VERSION 5.7 ;
  NOWIREEXTENSIONATPIN ON ;
  DIVIDERCHAR "/" ;
  BUSBITCHARS "[]" ;
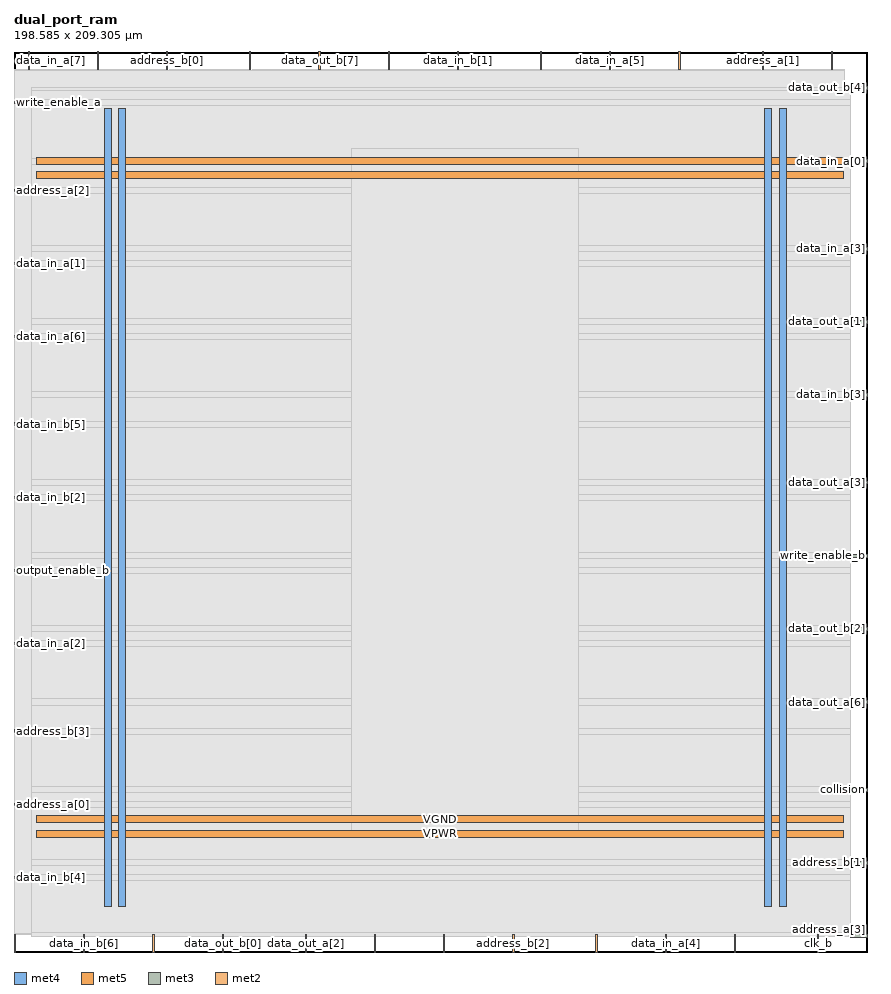
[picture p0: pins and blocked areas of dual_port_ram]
MACRO dual_port_ram
  CLASS BLOCK ;
  FOREIGN dual_port_ram ;
  ORIGIN 0.000 0.000 ;
  SIZE 198.585 BY 209.305 ;
  PIN VGND
    DIRECTION INOUT ;
    USE GROUND ;
    PORT
      LAYER met4 ;
        RECT 24.340 10.640 25.940 196.080 ;
    END
    PORT
      LAYER met4 ;
        RECT 177.940 10.640 179.540 196.080 ;
    END
    PORT
      LAYER met5 ;
        RECT 5.280 30.030 192.980 31.630 ;
    END
    PORT
      LAYER met5 ;
        RECT 5.280 183.210 192.980 184.810 ;
    END
  END VGND
  PIN VPWR
    DIRECTION INOUT ;
    USE POWER ;
    PORT
      LAYER met4 ;
        RECT 21.040 10.640 22.640 196.080 ;
    END
    PORT
      LAYER met4 ;
        RECT 174.640 10.640 176.240 196.080 ;
    END
    PORT
      LAYER met5 ;
        RECT 5.280 26.730 192.980 28.330 ;
    END
    PORT
      LAYER met5 ;
        RECT 5.280 179.910 192.980 181.510 ;
    END
  END VPWR
  PIN address_a[0]
    DIRECTION INPUT ;
    USE SIGNAL ;
    ANTENNAGATEAREA 0.247500 ;
    PORT
      LAYER met3 ;
        RECT 0.000 34.040 4.000 34.640 ;
    END
  END address_a[0]
  PIN address_a[1]
    DIRECTION INPUT ;
    USE SIGNAL ;
    ANTENNAGATEAREA 0.247500 ;
    PORT
      LAYER met2 ;
        RECT 173.970 205.305 174.250 209.305 ;
    END
  END address_a[1]
  PIN address_a[2]
    DIRECTION INPUT ;
    USE SIGNAL ;
    ANTENNAGATEAREA 0.213000 ;
    PORT
      LAYER met3 ;
        RECT 0.000 176.840 4.000 177.440 ;
    END
  END address_a[2]
  PIN address_a[3]
    DIRECTION INPUT ;
    USE SIGNAL ;
    ANTENNAGATEAREA 0.159000 ;
    PORT
      LAYER met3 ;
        RECT 194.585 3.440 198.585 4.040 ;
    END
  END address_a[3]
  PIN address_b[0]
    DIRECTION INPUT ;
    USE SIGNAL ;
    ANTENNAGATEAREA 0.213000 ;
    PORT
      LAYER met2 ;
        RECT 35.510 205.305 35.790 209.305 ;
    END
  END address_b[0]
  PIN address_b[1]
    DIRECTION INPUT ;
    USE SIGNAL ;
    ANTENNAGATEAREA 0.213000 ;
    PORT
      LAYER met3 ;
        RECT 194.585 20.440 198.585 21.040 ;
    END
  END address_b[1]
  PIN address_b[2]
    DIRECTION INPUT ;
    USE SIGNAL ;
    ANTENNAGATEAREA 0.159000 ;
    PORT
      LAYER met2 ;
        RECT 116.010 0.000 116.290 4.000 ;
    END
  END address_b[2]
  PIN address_b[3]
    DIRECTION INPUT ;
    USE SIGNAL ;
    ANTENNAGATEAREA 0.213000 ;
    PORT
      LAYER met3 ;
        RECT 0.000 51.040 4.000 51.640 ;
    END
  END address_b[3]
  PIN clk_a
    DIRECTION INPUT ;
    USE SIGNAL ;
    ANTENNAGATEAREA 0.852000 ;
    PORT
      LAYER met2 ;
        RECT 19.410 205.305 19.690 209.305 ;
    END
  END clk_a
  PIN clk_b
    DIRECTION INPUT ;
    USE SIGNAL ;
    ANTENNAGATEAREA 0.196500 ;
    PORT
      LAYER met2 ;
        RECT 186.850 0.000 187.130 4.000 ;
    END
  END clk_b
  PIN collision
    DIRECTION OUTPUT TRISTATE ;
    USE SIGNAL ;
    ANTENNADIFFAREA 0.445500 ;
    PORT
      LAYER met3 ;
        RECT 194.585 37.440 198.585 38.040 ;
    END
  END collision
  PIN data_in_a[0]
    DIRECTION INPUT ;
    USE SIGNAL ;
    ANTENNAGATEAREA 0.213000 ;
    PORT
      LAYER met3 ;
        RECT 194.585 183.640 198.585 184.240 ;
    END
  END data_in_a[0]
  PIN data_in_a[1]
    DIRECTION INPUT ;
    USE SIGNAL ;
    ANTENNAGATEAREA 0.213000 ;
    PORT
      LAYER met3 ;
        RECT 0.000 159.840 4.000 160.440 ;
    END
  END data_in_a[1]
  PIN data_in_a[2]
    DIRECTION INPUT ;
    USE SIGNAL ;
    ANTENNAGATEAREA 0.159000 ;
    PORT
      LAYER met3 ;
        RECT 0.000 71.440 4.000 72.040 ;
    END
  END data_in_a[2]
  PIN data_in_a[3]
    DIRECTION INPUT ;
    USE SIGNAL ;
    ANTENNAGATEAREA 0.213000 ;
    PORT
      LAYER met3 ;
        RECT 194.585 163.240 198.585 163.840 ;
    END
  END data_in_a[3]
  PIN data_in_a[4]
    DIRECTION INPUT ;
    USE SIGNAL ;
    ANTENNAGATEAREA 0.159000 ;
    PORT
      LAYER met2 ;
        RECT 151.430 0.000 151.710 4.000 ;
    END
  END data_in_a[4]
  PIN data_in_a[5]
    DIRECTION INPUT ;
    USE SIGNAL ;
    ANTENNAGATEAREA 0.213000 ;
    PORT
      LAYER met2 ;
        RECT 138.550 205.305 138.830 209.305 ;
    END
  END data_in_a[5]
  PIN data_in_a[6]
    DIRECTION INPUT ;
    USE SIGNAL ;
    ANTENNAGATEAREA 0.213000 ;
    PORT
      LAYER met3 ;
        RECT 0.000 142.840 4.000 143.440 ;
    END
  END data_in_a[6]
  PIN data_in_a[7]
    DIRECTION INPUT ;
    USE SIGNAL ;
    ANTENNAGATEAREA 0.159000 ;
    PORT
      LAYER met2 ;
        RECT 3.310 205.305 3.590 209.305 ;
    END
  END data_in_a[7]
  PIN data_in_b[0]
    DIRECTION INPUT ;
    USE SIGNAL ;
    ANTENNAGATEAREA 0.159000 ;
    PORT
      LAYER met2 ;
        RECT 154.650 205.305 154.930 209.305 ;
    END
  END data_in_b[0]
  PIN data_in_b[1]
    DIRECTION INPUT ;
    USE SIGNAL ;
    ANTENNAGATEAREA 0.159000 ;
    PORT
      LAYER met2 ;
        RECT 103.130 205.305 103.410 209.305 ;
    END
  END data_in_b[1]
  PIN data_in_b[2]
    DIRECTION INPUT ;
    USE SIGNAL ;
    ANTENNAGATEAREA 0.159000 ;
    PORT
      LAYER met3 ;
        RECT 0.000 105.440 4.000 106.040 ;
    END
  END data_in_b[2]
  PIN data_in_b[3]
    DIRECTION INPUT ;
    USE SIGNAL ;
    ANTENNAGATEAREA 0.213000 ;
    PORT
      LAYER met3 ;
        RECT 194.585 129.240 198.585 129.840 ;
    END
  END data_in_b[3]
  PIN data_in_b[4]
    DIRECTION INPUT ;
    USE SIGNAL ;
    ANTENNAGATEAREA 0.213000 ;
    PORT
      LAYER met3 ;
        RECT 0.000 17.040 4.000 17.640 ;
    END
  END data_in_b[4]
  PIN data_in_b[5]
    DIRECTION INPUT ;
    USE SIGNAL ;
    ANTENNAGATEAREA 0.159000 ;
    PORT
      LAYER met3 ;
        RECT 0.000 122.440 4.000 123.040 ;
    END
  END data_in_b[5]
  PIN data_in_b[6]
    DIRECTION INPUT ;
    USE SIGNAL ;
    ANTENNAGATEAREA 0.159000 ;
    PORT
      LAYER met2 ;
        RECT 16.190 0.000 16.470 4.000 ;
    END
  END data_in_b[6]
  PIN data_in_b[7]
    DIRECTION INPUT ;
    USE SIGNAL ;
    ANTENNAGATEAREA 0.159000 ;
    PORT
      LAYER met2 ;
        RECT 0.090 0.000 0.370 4.000 ;
    END
  END data_in_b[7]
  PIN data_out_a[0]
    DIRECTION OUTPUT TRISTATE ;
    USE SIGNAL ;
    ANTENNADIFFAREA 0.795200 ;
    PORT
      LAYER met2 ;
        RECT 87.030 205.305 87.310 209.305 ;
    END
  END data_out_a[0]
  PIN data_out_a[1]
    DIRECTION OUTPUT TRISTATE ;
    USE SIGNAL ;
    ANTENNADIFFAREA 0.445500 ;
    PORT
      LAYER met3 ;
        RECT 194.585 146.240 198.585 146.840 ;
    END
  END data_out_a[1]
  PIN data_out_a[2]
    DIRECTION OUTPUT TRISTATE ;
    USE SIGNAL ;
    ANTENNADIFFAREA 0.795200 ;
    PORT
      LAYER met2 ;
        RECT 67.710 0.000 67.990 4.000 ;
    END
  END data_out_a[2]
  PIN data_out_a[3]
    DIRECTION OUTPUT TRISTATE ;
    USE SIGNAL ;
    ANTENNADIFFAREA 0.445500 ;
    PORT
      LAYER met3 ;
        RECT 194.585 108.840 198.585 109.440 ;
    END
  END data_out_a[3]
  PIN data_out_a[4]
    DIRECTION OUTPUT TRISTATE ;
    USE SIGNAL ;
    ANTENNADIFFAREA 0.795200 ;
    PORT
      LAYER met2 ;
        RECT 167.530 0.000 167.810 4.000 ;
    END
  END data_out_a[4]
  PIN data_out_a[5]
    DIRECTION OUTPUT TRISTATE ;
    USE SIGNAL ;
    ANTENNADIFFAREA 0.795200 ;
    PORT
      LAYER met2 ;
        RECT 122.450 205.305 122.730 209.305 ;
    END
  END data_out_a[5]
  PIN data_out_a[6]
    DIRECTION OUTPUT TRISTATE ;
    USE SIGNAL ;
    ANTENNADIFFAREA 0.445500 ;
    PORT
      LAYER met3 ;
        RECT 194.585 57.840 198.585 58.440 ;
    END
  END data_out_a[6]
  PIN data_out_a[7]
    DIRECTION OUTPUT TRISTATE ;
    USE SIGNAL ;
    ANTENNADIFFAREA 0.795200 ;
    PORT
      LAYER met2 ;
        RECT 32.290 0.000 32.570 4.000 ;
    END
  END data_out_a[7]
  PIN data_out_b[0]
    DIRECTION OUTPUT TRISTATE ;
    USE SIGNAL ;
    ANTENNADIFFAREA 0.795200 ;
    PORT
      LAYER met2 ;
        RECT 48.390 0.000 48.670 4.000 ;
    END
  END data_out_b[0]
  PIN data_out_b[1]
    DIRECTION OUTPUT TRISTATE ;
    USE SIGNAL ;
    ANTENNADIFFAREA 0.795200 ;
    PORT
      LAYER met2 ;
        RECT 83.810 0.000 84.090 4.000 ;
    END
  END data_out_b[1]
  PIN data_out_b[2]
    DIRECTION OUTPUT TRISTATE ;
    USE SIGNAL ;
    ANTENNADIFFAREA 0.795200 ;
    PORT
      LAYER met3 ;
        RECT 194.585 74.840 198.585 75.440 ;
    END
  END data_out_b[2]
  PIN data_out_b[3]
    DIRECTION OUTPUT TRISTATE ;
    USE SIGNAL ;
    ANTENNADIFFAREA 0.795200 ;
    PORT
      LAYER met2 ;
        RECT 99.910 0.000 100.190 4.000 ;
    END
  END data_out_b[3]
  PIN data_out_b[4]
    DIRECTION OUTPUT TRISTATE ;
    USE SIGNAL ;
    ANTENNADIFFAREA 0.795200 ;
    PORT
      LAYER met3 ;
        RECT 194.585 200.640 198.585 201.240 ;
    END
  END data_out_b[4]
  PIN data_out_b[5]
    DIRECTION OUTPUT TRISTATE ;
    USE SIGNAL ;
    ANTENNADIFFAREA 0.445500 ;
    PORT
      LAYER met2 ;
        RECT 190.070 205.305 190.350 209.305 ;
    END
  END data_out_b[5]
  PIN data_out_b[6]
    DIRECTION OUTPUT TRISTATE ;
    USE SIGNAL ;
    ANTENNADIFFAREA 0.795200 ;
    PORT
      LAYER met2 ;
        RECT 54.830 205.305 55.110 209.305 ;
    END
  END data_out_b[6]
  PIN data_out_b[7]
    DIRECTION OUTPUT TRISTATE ;
    USE SIGNAL ;
    ANTENNADIFFAREA 0.795200 ;
    PORT
      LAYER met2 ;
        RECT 70.930 205.305 71.210 209.305 ;
    END
  END data_out_b[7]
  PIN output_enable_a
    DIRECTION INPUT ;
    USE SIGNAL ;
    ANTENNAGATEAREA 0.247500 ;
    PORT
      LAYER met2 ;
        RECT 135.330 0.000 135.610 4.000 ;
    END
  END output_enable_a
  PIN output_enable_b
    DIRECTION INPUT ;
    USE SIGNAL ;
    ANTENNAGATEAREA 0.213000 ;
    PORT
      LAYER met3 ;
        RECT 0.000 88.440 4.000 89.040 ;
    END
  END output_enable_b
  PIN write_enable_a
    DIRECTION INPUT ;
    USE SIGNAL ;
    ANTENNAGATEAREA 0.159000 ;
    PORT
      LAYER met3 ;
        RECT 0.000 197.240 4.000 197.840 ;
    END
  END write_enable_a
  PIN write_enable_b
    DIRECTION INPUT ;
    USE SIGNAL ;
    ANTENNAGATEAREA 0.213000 ;
    PORT
      LAYER met3 ;
        RECT 194.585 91.840 198.585 92.440 ;
    END
  END write_enable_b
  OBS
      LAYER li1 ;
        RECT 5.520 10.795 192.740 195.925 ;
      LAYER met1 ;
        RECT 0.070 10.640 193.130 196.080 ;
      LAYER met2 ;
        RECT 0.100 205.025 3.030 205.305 ;
        RECT 3.870 205.025 19.130 205.305 ;
        RECT 19.970 205.025 35.230 205.305 ;
        RECT 36.070 205.025 54.550 205.305 ;
        RECT 55.390 205.025 70.650 205.305 ;
        RECT 71.490 205.025 86.750 205.305 ;
        RECT 87.590 205.025 102.850 205.305 ;
        RECT 103.690 205.025 122.170 205.305 ;
        RECT 123.010 205.025 138.270 205.305 ;
        RECT 139.110 205.025 154.370 205.305 ;
        RECT 155.210 205.025 173.690 205.305 ;
        RECT 174.530 205.025 189.790 205.305 ;
        RECT 190.630 205.025 193.110 205.305 ;
        RECT 0.100 4.280 193.110 205.025 ;
        RECT 0.650 4.000 15.910 4.280 ;
        RECT 16.750 4.000 32.010 4.280 ;
        RECT 32.850 4.000 48.110 4.280 ;
        RECT 48.950 4.000 67.430 4.280 ;
        RECT 68.270 4.000 83.530 4.280 ;
        RECT 84.370 4.000 99.630 4.280 ;
        RECT 100.470 4.000 115.730 4.280 ;
        RECT 116.570 4.000 135.050 4.280 ;
        RECT 135.890 4.000 151.150 4.280 ;
        RECT 151.990 4.000 167.250 4.280 ;
        RECT 168.090 4.000 186.570 4.280 ;
        RECT 187.410 4.000 193.110 4.280 ;
      LAYER met3 ;
        RECT 3.990 200.240 194.185 201.105 ;
        RECT 3.990 198.240 194.585 200.240 ;
        RECT 4.400 196.840 194.585 198.240 ;
        RECT 3.990 184.640 194.585 196.840 ;
        RECT 3.990 183.240 194.185 184.640 ;
        RECT 3.990 177.840 194.585 183.240 ;
        RECT 4.400 176.440 194.585 177.840 ;
        RECT 3.990 164.240 194.585 176.440 ;
        RECT 3.990 162.840 194.185 164.240 ;
        RECT 3.990 160.840 194.585 162.840 ;
        RECT 4.400 159.440 194.585 160.840 ;
        RECT 3.990 147.240 194.585 159.440 ;
        RECT 3.990 145.840 194.185 147.240 ;
        RECT 3.990 143.840 194.585 145.840 ;
        RECT 4.400 142.440 194.585 143.840 ;
        RECT 3.990 130.240 194.585 142.440 ;
        RECT 3.990 128.840 194.185 130.240 ;
        RECT 3.990 123.440 194.585 128.840 ;
        RECT 4.400 122.040 194.585 123.440 ;
        RECT 3.990 109.840 194.585 122.040 ;
        RECT 3.990 108.440 194.185 109.840 ;
        RECT 3.990 106.440 194.585 108.440 ;
        RECT 4.400 105.040 194.585 106.440 ;
        RECT 3.990 92.840 194.585 105.040 ;
        RECT 3.990 91.440 194.185 92.840 ;
        RECT 3.990 89.440 194.585 91.440 ;
        RECT 4.400 88.040 194.585 89.440 ;
        RECT 3.990 75.840 194.585 88.040 ;
        RECT 3.990 74.440 194.185 75.840 ;
        RECT 3.990 72.440 194.585 74.440 ;
        RECT 4.400 71.040 194.585 72.440 ;
        RECT 3.990 58.840 194.585 71.040 ;
        RECT 3.990 57.440 194.185 58.840 ;
        RECT 3.990 52.040 194.585 57.440 ;
        RECT 4.400 50.640 194.585 52.040 ;
        RECT 3.990 38.440 194.585 50.640 ;
        RECT 3.990 37.040 194.185 38.440 ;
        RECT 3.990 35.040 194.585 37.040 ;
        RECT 4.400 33.640 194.585 35.040 ;
        RECT 3.990 21.440 194.585 33.640 ;
        RECT 3.990 20.040 194.185 21.440 ;
        RECT 3.990 18.040 194.585 20.040 ;
        RECT 4.400 16.640 194.585 18.040 ;
        RECT 3.990 4.440 194.585 16.640 ;
        RECT 3.990 3.590 194.185 4.440 ;
      LAYER met4 ;
        RECT 78.495 27.375 131.265 186.825 ;
  END
END dual_port_ram
END LIBRARY

